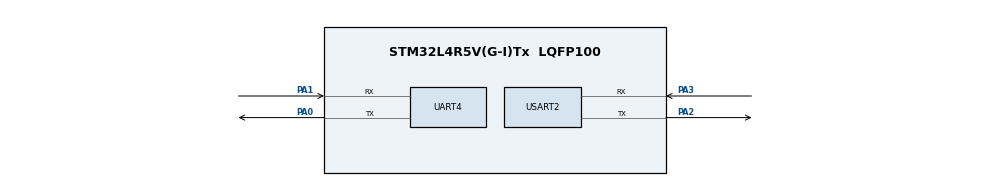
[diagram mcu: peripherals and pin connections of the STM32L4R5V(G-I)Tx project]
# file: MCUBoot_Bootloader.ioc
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IWDG.Prescaler=IWDG_PRESCALER_32
IWDG.Reload=1250
Mcu.Family=STM32L4
Mcu.Name=STM32L4R5V(G-I)Tx
Mcu.Package=LQFP100
NVIC.PriorityGroup=NVIC_PRIORITYGROUP_4
PA0.Mode=Asynchronous
PA0.Signal=UART4_TX
PA1.Mode=Asynchronous
PA1.Signal=UART4_RX
PA13\ (JTMS/SWDIO).Mode=Serial_Wire
PA13\ (JTMS/SWDIO).Signal=SYS_JTMS-SWDIO
PA14\ (JTCK/SWCLK).Mode=Serial_Wire
PA14\ (JTCK/SWCLK).Signal=SYS_JTCK-SWCLK
PA2.Mode=Asynchronous
PA2.Signal=USART2_TX
PA3.Mode=Asynchronous
PA3.Signal=USART2_RX
PH0-OSC_IN\ (PH0).Mode=HSE-External-Oscillator
PH0-OSC_IN\ (PH0).Signal=RCC_OSC_IN
PH1-OSC_OUT\ (PH1).Mode=HSE-External-Oscillator
PH1-OSC_OUT\ (PH1).Signal=RCC_OSC_OUT
ProjectManager.HeapSize=0x200
ProjectManager.StackSize=0x400
ProjectManager.TargetToolchain=STM32CubeIDE
RCC.ADCFreq_Value=64000000
RCC.AHBFreq_Value=16000000
RCC.APB1Freq_Value=16000000
RCC.APB1TimFreq_Value=16000000
RCC.APB2Freq_Value=16000000
RCC.APB2TimFreq_Value=16000000
RCC.CortexFreq_Value=16000000
RCC.HCLKFreq_Value=16000000
RCC.HSE_VALUE=8000000
RCC.HSI48_VALUE=48000000
RCC.HSI_VALUE=16000000
RCC.LSE_VALUE=32768
RCC.MSI_VALUE=4000000
RCC.PLLSourceVirtual=RCC_PLLSOURCE_HSI
RCC.PREFETCH_ENABLE=1
RCC.SYSCLKFreq_VALUE=16000000
RCC.SYSCLKSource=RCC_SYSCLKSOURCE_HSI
RCC.USBFreq_Value=64000000
RCC.VCOOutputFreq_Value=128000000
USART2.VirtualMode-Asynchronous=VM_ASYNC
VP_IWDG_VS_IWDG.Mode=IWDG_Activate
board=custom

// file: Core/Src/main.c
/* USER CODE BEGIN Header */
/**
  ******************************************************************************
  * @file           : main.c
  * @brief          : Main program body
  ******************************************************************************
  * @attention
  *
  * Copyright (c) 2026 STMicroelectronics.
  * All rights reserved.
  *
  * This software is licensed under terms that can be found in the LICENSE file
  * in the root directory of this software component.
  * If no LICENSE file comes with this software, it is provided AS-IS.
  *
  ******************************************************************************
  */
/* USER CODE END Header */
#include "main.h"
#include "iwdg.h"
#include "usart.h"
#include "gpio.h"
#include "../../MCUBoot/bootutil/include/bootutil/bootutil.h"  /* boot_go() */
#include "../../MCUBoot/flash_map_backend/boot_hal.h"            /* boot_hal_jump_to_app() */
#include "../../MCUBoot/mcuboot_config/mcuboot_config.h"
#include <stdio.h>

void SystemClock_Config(void);

/* ================================================================
 * REDIRECTION printf → UART4 (pour les logs MCUBoot)
 * ================================================================ */
int _write(int file, char *ptr, int len)
{
    (void)file;
    HAL_UART_Transmit(&huart4, (uint8_t *)ptr, (uint16_t)len, 1000);
    return len;
}

void mcuboot_watchdog_feed(void)
{
//    HAL_IWDG_Refresh(&hiwdg);
}

int main(void)
{
  struct boot_rsp boot_response;
  int             boot_result;
  uint32_t        app_start;

  /* MCU Configuration--------------------------------------------------------*/

  /* Reset of all peripherals, Initializes the Flash interface and the Systick. */
  HAL_Init();
//  setbuf(stdout, NULL);

  /* Configure the system clock */
  SystemClock_Config();

  /* Initialize all configured peripherals */
  MX_GPIO_Init();
  MX_IWDG_Init();
  MX_USART2_UART_Init();
  MX_UART4_Init();

  HAL_Delay(500);
  HAL_IWDG_Refresh(&hiwdg);

  /* ----------------------------------------------------------
    * 2. Bannière de démarrage
    * ---------------------------------------------------------- */
   MCUBOOT_LOG_INF("========================================");
   MCUBOOT_LOG_INF(" Secure Bootloader — STM32L4R5VGT6");
   MCUBOOT_LOG_INF(" MCUBoot v2.1.0 / ECDSA-P256");
   MCUBOOT_LOG_INF("========================================");

   /* Vérification image */
   MCUBOOT_LOG_INF("Verification de l image en cours...");

   /* ----------------------------------------------------------
    * 3. Nourrir le watchdog avant une opération longue
    * ---------------------------------------------------------- */
   HAL_IWDG_Refresh(&hiwdg);
//   HAL_Delay(2000);
   /*
      * mcuboot_watchdog_feed()
      * Appelée par MCUBoot pendant les opérations longues (swap, erase).
      * Permet à hiwdg de rester dans main.c sans export global.
      */

   /* ----------------------------------------------------------
       * 4. Appel de la fonction principale MCUBoot
       *
       *    boot_go() effectue dans l'ordre :
       *      a) Vérification de la signature du Slot 0 (ECDSA-P256)
       *      b) Vérification du hash SHA-256 de l'image
       *      c) Si une image en attente est dans le Slot 1 :
       *           → Swap Slot 1 → Slot 0 (via SWAP_USING_MOVE)
       *           → Redémarre depuis le Slot 0 mis à jour
       *      d) Remplit boot_response avec l'adresse de démarrage
   * ---------------------------------------------------------- */
//   MCUBOOT_LOG_INF("Vérification de l'image en cours...");

   boot_result = boot_go(&boot_response);
   HAL_IWDG_Refresh(&hiwdg);
     /* ----------------------------------------------------------
      * 5. Analyse du résultat
      * ---------------------------------------------------------- */
   if (boot_result != 0) {
       MCUBOOT_LOG_ERR("boot_go() ÉCHEC (code=%d)", boot_result);
       MCUBOOT_LOG_ERR("Aucune image valide trouvée — système bloqué");
       MCUBOOT_LOG_ERR("Attente du reset watchdog...");

         /* Bloquer — le IWDG va resetter dans ~5 secondes */
       while (1) {
           __NOP();
       }
   }

   /* ----------------------------------------------------------
        * 6. Image valide — calcul de l'adresse de saut
        *
        *    boot_response.br_image_off : offset du début de l'image
        *    boot_response.br_hdr       : pointeur vers le header MCUBoot
        *    boot_response.br_hdr->ih_hdr_size : taille du header (0x400)
        *
        *    app_start = base Flash + offset image + taille header
    * ---------------------------------------------------------- */
   app_start = FLASH_BASE_ADDRESS
             + boot_response.br_image_off
             + boot_response.br_hdr->ih_hdr_size;

   MCUBOOT_LOG_INF("Image valide — version %d.%d.%d",
                   boot_response.br_hdr->ih_ver.iv_major,
                   boot_response.br_hdr->ih_ver.iv_minor,
                   boot_response.br_hdr->ih_ver.iv_revision);
   MCUBOOT_LOG_INF("Adresse de saut : 0x%08X", app_start);

   MCUBOOT_LOG_INF("SP app        = 0x%08X",
                   *(volatile uint32_t *)app_start);
   MCUBOOT_LOG_INF("Reset handler = 0x%08X",
                   *(volatile uint32_t *)(app_start + 4));
       /* ----------------------------------------------------------
        * 7. Nourrir le watchdog une dernière fois avant le saut
        * ---------------------------------------------------------- */
   HAL_IWDG_Refresh(&hiwdg);
//   HAL_Delay(2000);
       /* ----------------------------------------------------------
        * 8. SAUT VERS L'APPLICATION — aucun retour après cette ligne
        * ---------------------------------------------------------- */
   boot_hal_jump_to_app(app_start);

       /* Ne doit jamais être atteint */
   while (1) { __NOP(); }
}

void SystemClock_Config(void)
{
    RCC_OscInitTypeDef RCC_OscInitStruct = {0};
    RCC_ClkInitTypeDef RCC_ClkInitStruct = {0};

    /* Voltage scaling Range 1 pour 80 MHz */
    if (HAL_PWREx_ControlVoltageScaling(PWR_REGULATOR_VOLTAGE_SCALE1) != HAL_OK) {
        Error_Handler();
    }

    /* HSI 16 MHz + PLL → 80 MHz */
    RCC_OscInitStruct.OscillatorType      = RCC_OSCILLATORTYPE_HSI
                                          | RCC_OSCILLATORTYPE_LSI;
    RCC_OscInitStruct.HSIState            = RCC_HSI_ON;
    RCC_OscInitStruct.HSICalibrationValue = RCC_HSICALIBRATION_DEFAULT;
    RCC_OscInitStruct.LSIState            = RCC_LSI_ON;
    RCC_OscInitStruct.PLL.PLLState        = RCC_PLL_ON;
    RCC_OscInitStruct.PLL.PLLSource       = RCC_PLLSOURCE_HSI;
    RCC_OscInitStruct.PLL.PLLM            = 1;
    RCC_OscInitStruct.PLL.PLLN            = 10;
    RCC_OscInitStruct.PLL.PLLP            = RCC_PLLP_DIV7;
    RCC_OscInitStruct.PLL.PLLQ            = RCC_PLLQ_DIV2;
    RCC_OscInitStruct.PLL.PLLR            = RCC_PLLR_DIV2;

    if (HAL_RCC_OscConfig(&RCC_OscInitStruct) != HAL_OK) {
        Error_Handler();
    }

    /* SYSCLK = PLL = 80 MHz */
    RCC_ClkInitStruct.ClockType      = RCC_CLOCKTYPE_HCLK
                                     | RCC_CLOCKTYPE_SYSCLK
                                     | RCC_CLOCKTYPE_PCLK1
                                     | RCC_CLOCKTYPE_PCLK2;
    RCC_ClkInitStruct.SYSCLKSource   = RCC_SYSCLKSOURCE_PLLCLK;
    RCC_ClkInitStruct.AHBCLKDivider  = RCC_SYSCLK_DIV1;
    RCC_ClkInitStruct.APB1CLKDivider = RCC_HCLK_DIV1;
    RCC_ClkInitStruct.APB2CLKDivider = RCC_HCLK_DIV1;

    if (HAL_RCC_ClockConfig(&RCC_ClkInitStruct, FLASH_LATENCY_4) != HAL_OK) {
        Error_Handler();
    }
}

/* USER CODE BEGIN 4 */
/* Implement MMIO setup functions in the auto-generated peripheral files
 * (gpio.c, iwdg.c, usart.c) to avoid duplicate symbol definitions. */
/* USER CODE END 4 */

void Error_Handler(void)
{
  /* USER CODE BEGIN Error_Handler_Debug */
  /* User can add his own implementation to report the HAL error return state */
  __disable_irq();
  MCUBOOT_LOG_ERR("Error_Handler — reset imminent");
  while (1)
  {
	  __NOP();
  }
  /* USER CODE END Error_Handler_Debug */
}
